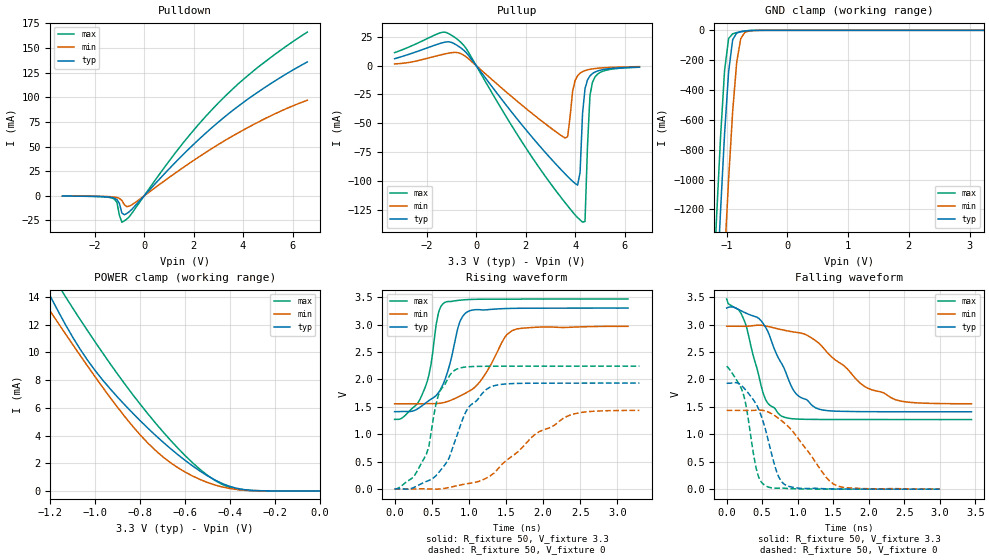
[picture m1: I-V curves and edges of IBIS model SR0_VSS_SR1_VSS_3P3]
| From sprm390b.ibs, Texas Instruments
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|   Model Cell SR0_VSS_SR1_VSS_3P3
|SR0_VSS_SR1_VSS_3P3
[Model]   SR0_VSS_SR1_VSS_3P3
Model_type   I/O
Polarity   Non-Inverting
Enable   Active-Low
Vinl =  0.8V
Vinh =  2V
Cref =  5.0000pF
Rref =  100.0000M
Vref =  0V
Vmeas =  1.65
C_comp   2.088321p   2.017362p   2.221145p
[Model Spec]
Vinl   0.8V   0.8V   0.8V
Vinh   2V   2V   2V
[Temperature Range]   25   125   -40
[Voltage Range]   3.3   2.97   3.465
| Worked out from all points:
|   slope of the pulldown table from 0 to 0.495 V, typ, clamps not added: 36.4 ohm
|   slope of the pullup table from 0 to 0.495 V, typ, clamps not added: 34.9 ohm
|   GND clamp passes 1 mA (typ) near -0.57 V on its own axis
|   POWER clamp passes 1 mA (typ) near -0.49 V on its own axis
|   rising waveform, R_fixture 50, V_fixture 3.3: 20-80 % time 244ps typ, 387ps min, 197ps max; typ from 1.41 V to 3.3 V
|   rising waveform, R_fixture 50, V_fixture 0: 20-80 % time 393ps typ, 793ps min, 263ps max; typ from 0 V to 1.93 V
|   falling waveform, R_fixture 50, V_fixture 3.3: 20-80 % time 387ps typ, 715ps min, 264ps max; typ from 3.3 V to 1.41 V
|   falling waveform, R_fixture 50, V_fixture 0: 20-80 % time 270ps typ, 497ps min, 185ps max; typ from 1.93 V to 0 V
[POWER_clamp]
|   voltage   I(typ)   I(min)   I(max)
-3.3V     86.08mA    64.51mA    104.3mA
-1.267V   16.23mA    14.61mA    17.94mA
-1.233V   15.14mA    13.79mA    16.86mA
-1.2V     14.07mA    12.98mA    15.86mA
-1.133V   12.04mA    11.37mA    14.06mA
-1V       8.693mA    8.239mA    10.76mA
-866.7mV  6.192mA    5.342mA    7.695mA
-766.7mV  4.556mA    3.483mA    5.603mA
-633.3mV  2.644mA    1.698mA    3.12mA
-500mV    1.095mA    613.6uA    1.135mA
-366.7mV  181.9uA    101.9uA    111.5uA
-11.55fV  484.7nA    452.9nA    508.6nA
[Pulldown]
|   voltage   I(typ)   I(min)   I(max)
-3.3V     -240.7uA   -171.6uA   -267.5uA
-1.3V     -1.697mA   -968uA     -2.239mA
-1.1V     -3.762mA   -1.687mA   -6.636mA
-1V       -7.727mA   -2.567mA   -19.64mA
-900mV    -17.44mA   -4.637mA   -26.73mA
-800mV    -19.19mA   -8.992mA   -25.39mA
-700mV    -17.88mA   -11mA      -23.57mA
-500mV    -13.74mA   -9.146mA   -17.83mA
1.4V      37.42mA    25.57mA    48.03mA
2.9V      72.6mA     50.52mA    91.53mA
4.6V      105.1mA    74.64mA    130.4mA
6.6V      135.8mA    96.92mA    166.1mA
[Pullup]
|   voltage   I(typ)   I(min)   I(max)
-3.3V     6.015mA    1.488mA    11.26mA
-1.4V     19.63mA    9.503mA    28.79mA
-700mV    16.55mA    11.01mA    21.71mA
3.6V      -93.97mA   -62.77mA   -119mA
4.1V      -103.6mA   -8.736mA   -131.8mA
4.2V      -92.66mA   -6.55mA    -133.7mA
4.3V      -41.55mA   -5.211mA   -135.8mA
4.4V      -19.91mA   -4.314mA   -135.1mA
4.5V      -12.4mA    -3.675mA   -69.72mA
4.6V      -8.868mA   -3.197mA   -25.86mA
4.7V      -6.864mA   -2.828mA   -14.55mA
6.6V      -1.25mA    -873.6uA   -1.41mA
[GND_clamp]
|   voltage   I(typ)   I(min)   I(max)
-3.3V     -22.46A    -23.25A    -22.02A
-1.233V   -2.372A    -3.255A    -1.856A
-1.167V   -1.78A     -2.658A    -1.268A
-1.1V     -1.214A    -2.077A    -719.3mA
-1.033V   -694.8mA   -1.519A    -269mA
-966.7mV  -277.7mA   -998.2mA   -54.71mA
-900mV    -62.85mA   -543.8mA   -23.11mA
-833.3mV  -17.76mA   -212.7mA   -15.05mA
-766.7mV  -9.254mA   -55.4mA    -9.029mA
-700mV    -5.096mA   -13.88mA   -4.435mA
-633.3mV  -2.353mA   -4.844mA   -1.587mA
3.233V    464.9nA    13.45uA    453.9nA
[Ramp]
| variable   typ   min   max
dV/dt_f   1.530224/0.7195842n   1.148064/1.235031n   1.776345/0.4937041n
dV/dt_r   1.548496/0.664374n   1.151877/1.13807n   1.796222/0.4649104n
R_load = 50
[Rising Waveform]
R_fixture = 50
V_fixture = 3.3
V_fixture_min = 2.97
V_fixture_max = 3.465
|   time   V(typ)   V(min)   V(max)
0s        1.411V     1.554V     1.269V
364ps     1.513V     1.555V     1.7V
462ps     1.612V     1.557V     2.077V
588ps     1.75V      1.56V      3.199V
679ps     1.998V     1.582V     3.405V
875ps     3.036V     1.691V     3.444V
1.015ns   3.253V     1.793V     3.457V
1.197ns   3.266V     2.047V     3.462V
1.582ns   3.295V     2.889V     3.464V
3.143ns   3.3V       2.967V     3.465V
[Rising Waveform]
R_fixture = 50
V_fixture = 0
V_fixture_min = 0
V_fixture_max = 0
|   time   V(typ)   V(min)   V(max)
0s        5.618uV    6.879uV    4.844uV
238ps     14.62mV    -57.69uV   199mV
427ps     136.4mV    1.76mV     629.7mV
588ps     289.8mV    -3.133mV   1.703V
826ps     922.2mV    53.85mV    2.179V
987ps     1.469V     98.26mV    2.229V
1.337ns   1.882V     286.6mV    2.239V
1.883ns   1.929V     986.8mV    2.241V
2.31ns    1.931V     1.317V     2.241V
3.297ns   1.931V     1.433V     2.241V
[Falling Waveform]
R_fixture = 50
V_fixture = 3.3
V_fixture_min = 2.97
V_fixture_max = 3.465
|   time   V(typ)   V(min)   V(max)
0s        3.3V       2.97V      3.465V
252ps     3.22V      2.969V     3.059V
455ps     3.11V      2.989V     2.052V
546ps     2.954V     2.975V     1.636V
777ps     2.281V     2.906V     1.329V
973ps     1.744V     2.859V     1.279V
1.309ns   1.454V     2.646V     1.271V
1.932ns   1.413V     1.878V     1.269V
2.366ns   1.411V     1.635V     1.269V
3.444ns   1.411V     1.557V     1.269V
[Falling Waveform]
R_fixture = 50
V_fixture = 0
V_fixture_min = 0
V_fixture_max = 0
|   time   V(typ)   V(min)   V(max)
0s        1.931V     1.436V     2.241V
224ps     1.869V     1.436V     1.776V
280ps     1.788V     1.435V     1.468V
420ps     1.538V     1.44V      353.3mV
546ps     1.086V     1.425V     63.16mV
721ps     258.1mV    1.299V     17.03mV
875ps     50.25mV    1.131V     10.76mV
1.407ns   7.252mV    206.3mV    1.482mV
1.575ns   3.763mV    51.31mV    1.042mV
2.996ns   371uV      3.039mV    124.8uV
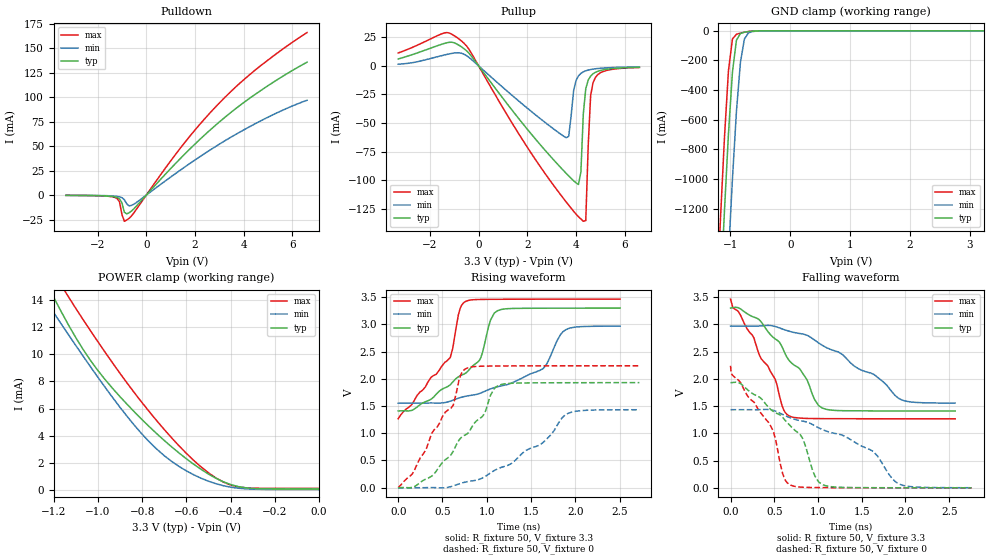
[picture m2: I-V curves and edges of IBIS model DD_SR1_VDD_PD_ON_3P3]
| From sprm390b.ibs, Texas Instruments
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|   Model Cell DD_SR1_VDD_PD_ON_3P3
|SR0_VDD_SR1_VDD_PD_ON_3P3
[Model]   DD_SR1_VDD_PD_ON_3P3
Model_type   I/O
Polarity   Non-Inverting
Enable   Active-Low
Vinl =  0.8V
Vinh =  2V
Cref =  5.0000pF
Rref =  100.0000M
Vref =  0V
Vmeas =  1.65
C_comp   2.113745p   2.040636p   2.247812p
[Model Spec]
Vinl   0.8V   0.8V   0.8V
Vinh   2V   2V   2V
[Temperature Range]   25   125   -40
[Voltage Range]   3.3   2.97   3.465
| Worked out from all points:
|   slope of the pulldown table from 0 to 0.495 V, typ, clamps not added: 36.4 ohm
|   slope of the pullup table from 0 to 0.495 V, typ, clamps not added: 34.9 ohm
|   GND clamp passes 1 mA (typ) near -0.57 V on its own axis
|   POWER clamp passes 1 mA (typ) near -0.48 V on its own axis
|   rising waveform, R_fixture 50, V_fixture 3.3: 20-80 % time 539ps typ, 708ps min, 443ps max; typ from 1.41 V to 3.3 V
|   rising waveform, R_fixture 50, V_fixture 0: 20-80 % time 549ps typ, 739ps min, 445ps max; typ from 0 V to 1.93 V
|   falling waveform, R_fixture 50, V_fixture 3.3: 20-80 % time 516ps typ, 825ps min, 402ps max; typ from 3.3 V to 1.41 V
|   falling waveform, R_fixture 50, V_fixture 0: 20-80 % time 526ps typ, 842ps min, 410ps max; typ from 1.93 V to 0.001 V
[POWER_clamp]
|   voltage   I(typ)   I(min)   I(max)
-3.3V     86.18mA    64.56mA    104.4mA
-1.267V   16.33mA    14.66mA    18.08mA
-1.233V   15.23mA    13.85mA    17mA
-1.2V     14.16mA    13.03mA    16mA
-1.133V   12.14mA    11.42mA    14.2mA
-1V       8.786mA    8.291mA    10.9mA
-866.7mV  6.286mA    5.394mA    7.837mA
-766.7mV  4.65mA     3.535mA    5.745mA
-633.3mV  2.737mA    1.75mA     3.262mA
-500mV    1.189mA    665.2uA    1.278mA
-366.7mV  275.7uA    153.6uA    253.8uA
-11.55fV  94.2uA     52.09uA    142.8uA
[Pulldown]
|   voltage   I(typ)   I(min)   I(max)
-3.3V     -240.7uA   -171.6uA   -267.5uA
-1.3V     -1.697mA   -968uA     -2.239mA
-1.1V     -3.762mA   -1.687mA   -6.637mA
-1V       -7.728mA   -2.567mA   -19.64mA
-900mV    -17.44mA   -4.637mA   -26.73mA
-800mV    -19.19mA   -8.992mA   -25.39mA
-700mV    -17.88mA   -11mA      -23.57mA
-500mV    -13.74mA   -9.146mA   -17.83mA
1.4V      37.42mA    25.57mA    48.03mA
2.9V      72.6mA     50.52mA    91.53mA
4.6V      105.1mA    74.64mA    130.4mA
6.6V      135.8mA    96.92mA    166.1mA
[Pullup]
|   voltage   I(typ)   I(min)   I(max)
-3.3V     6.015mA    1.488mA    11.26mA
-1.4V     19.63mA    9.503mA    28.79mA
-700mV    16.55mA    11.01mA    21.71mA
3.6V      -93.97mA   -62.77mA   -119mA
4.1V      -103.6mA   -8.736mA   -131.8mA
4.2V      -92.66mA   -6.551mA   -133.7mA
4.3V      -41.56mA   -5.211mA   -135.8mA
4.4V      -19.91mA   -4.314mA   -135.1mA
4.5V      -12.4mA    -3.675mA   -69.73mA
4.6V      -8.869mA   -3.197mA   -25.87mA
4.7V      -6.864mA   -2.828mA   -14.55mA
6.6V      -1.25mA    -873.6uA   -1.41mA
[GND_clamp]
|   voltage   I(typ)   I(min)   I(max)
-3.3V     -22.46A    -23.25A    -22.02A
-1.233V   -2.372A    -3.255A    -1.856A
-1.167V   -1.78A     -2.658A    -1.268A
-1.1V     -1.214A    -2.077A    -719.3mA
-1.033V   -694.9mA   -1.519A    -269mA
-966.7mV  -277.7mA   -998.2mA   -54.82mA
-900mV    -62.93mA   -543.8mA   -23.21mA
-833.3mV  -17.83mA   -212.7mA   -15.14mA
-766.7mV  -9.317mA   -55.45mA   -9.115mA
-700mV    -5.152mA   -13.93mA   -4.514mA
-633.3mV  -2.404mA   -4.879mA   -1.658mA
3.233V    94.16uA    65.13uA    142.7uA
[Ramp]
| variable   typ   min   max
dV/dt_f   1.523355/0.6834145n   1.142835/1.117289n   1.768965/0.5169915n
dV/dt_r   1.545562/0.6945306n   1.149676/0.9660131n   1.792774/0.5502105n
R_load = 50
[Rising Waveform]
R_fixture = 50
V_fixture = 3.3
V_fixture_min = 2.97
V_fixture_max = 3.465
|   time   V(typ)   V(min)   V(max)
0s        1.409V     1.553V     1.267V
588ps     1.89V      1.589V     2.391V
679ps     2.036V     1.643V     3.171V
749ps     2.091V     1.675V     3.408V
931ps     2.381V     1.738V     3.456V
1.043ns   3.081V     1.814V     3.458V
1.12ns    3.248V     1.853V     3.459V
1.638ns   3.295V     2.189V     3.462V
1.89ns    3.296V     2.899V     3.462V
2.506ns   3.297V     2.966V     3.462V
[Rising Waveform]
R_fixture = 50
V_fixture = 0
V_fixture_min = 0
V_fixture_max = 0
|   time   V(typ)   V(min)   V(max)
0s        5.609uV    6.87uV     4.835uV
161ps     4.625mV    -39.19uV   257.1mV
378ps     211.5mV    2.892mV    996.8mV
623ps     674.4mV    34.16mV    1.519V
707ps     914.4mV    80.58mV    2.077V
777ps     988.2mV    109.6mV    2.195V
1.162ns   1.894V     372.6mV    2.235V
1.645ns   1.926V     843.9mV    2.238V
1.918ns   1.928V     1.365V     2.238V
2.723ns   1.929V     1.431V     2.239V
[Falling Waveform]
R_fixture = 50
V_fixture = 3.3
V_fixture_min = 2.97
V_fixture_max = 3.465
|   time   V(typ)   V(min)   V(max)
0s        3.298V     2.969V     3.463V
322ps     3.094V     2.969V     2.465V
511ps     2.732V     2.96V      1.992V
588ps     2.592V     2.917V     1.513V
665ps     2.348V     2.876V     1.325V
868ps     1.999V     2.804V     1.274V
1.008ns   1.508V     2.658V     1.271V
1.099ns   1.439V     2.571V     1.27V
1.96ns    1.41V      1.612V     1.267V
2.569ns   1.41V      1.556V     1.267V
[Falling Waveform]
R_fixture = 50
V_fixture = 0
V_fixture_min = 0
V_fixture_max = 0
|   time   V(typ)   V(min)   V(max)
0s        1.93V      1.434V     2.239V
462ps     1.435V     1.433V     1.127V
595ps     1.295V     1.347V     267.1mV
686ps     1.135V     1.283V     51.41mV
819ps     922.9mV    1.226V     12.55mV
966ps     212.7mV    1.137V     6.108mV
1.057ns   55.56mV    1.066V     4.704mV
1.631ns   3.37mV     669.1mV    1.466mV
1.932ns   2.062mV    67.18mV    841.4uV
2.758ns   753.9uV    2.997mV    245.1uV
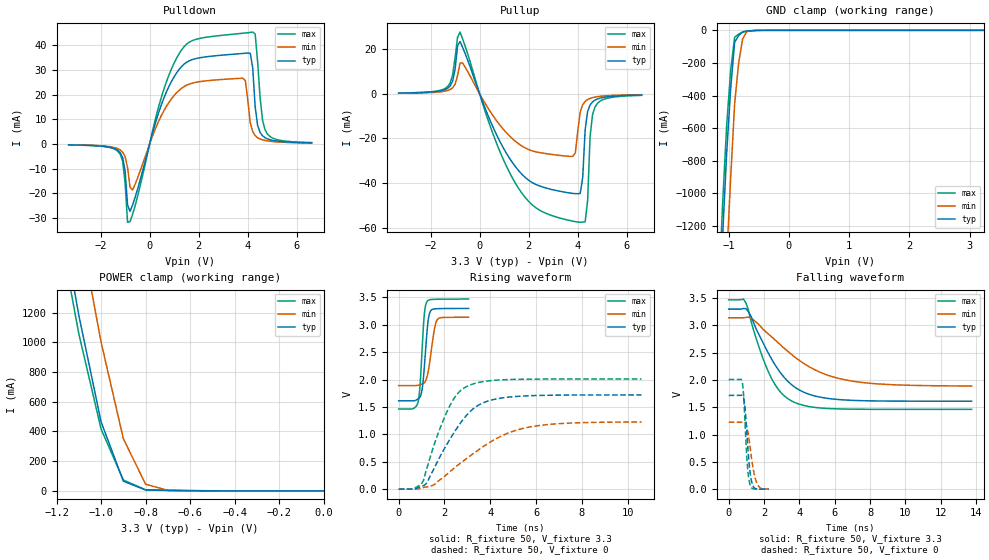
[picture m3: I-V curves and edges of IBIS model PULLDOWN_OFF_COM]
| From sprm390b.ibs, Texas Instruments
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|   Model Cell PULLDOWN_OFF_COM
[Model]   PULLDOWN_OFF_COM
Model_type   I/O
Polarity   Non-Inverting
Enable   Active-Low
Vinl =  0.8
Vinh =  2
Cref =  15.0000pF
Rref =  100.0000M
Vref =  0V
Vmeas =  1.65
C_comp   0.8695239p   0.8563616p   0.8781626p
[Model Spec]
Vinl   0.8   0.8   0.8
Vinh   2   2   2
[Temperature Range]   25   105   0
[Voltage Range]   3.3   3.14   3.47
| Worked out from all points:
|   slope of the pulldown table from 0 to 0.495 V, typ, clamps not added: 30.2 ohm
|   slope of the pullup table from 0 to 0.495 V, typ, clamps not added: 36.2 ohm
|   GND clamp passes 1 mA (typ) near -0.57 V on its own axis
|   POWER clamp passes 1 mA (typ) near -0.52 V on its own axis
|   rising waveform, R_fixture 50, V_fixture 3.3: 20-80 % time 195ps typ, 262ps min, 169ps max; typ from 1.61 V to 3.3 V
|   rising waveform, R_fixture 50, V_fixture 0: 20-80 % time 1.52ns typ, 2.51ns min, 1.1ns max; typ from 0 V to 1.72 V
|   falling waveform, R_fixture 50, V_fixture 3.3: 20-80 % time 1.92ns typ, 3.11ns min, 1.46ns max; typ from 3.3 V to 1.61 V
|   falling waveform, R_fixture 50, V_fixture 0: 20-80 % time 242ps typ, 346ps min, 204ps max; typ from 1.72 V to 0.002 V
[POWER_clamp]
|   voltage   I(typ)   I(min)   I(max)
-3.3V     22.37A     22.96A     22.21A
-1.133V   1.464A     2.096A     1.329A
-1.1V     1.183A     1.806A     1.058A
-1.067V   943.8mA    1.538A     844.6mA
-1.033V   704.5mA    1.27A      630.9mA
-1V       465.3mA    1.002A     417.3mA
-900mV    65.74mA    351.8mA    73.25mA
-800mV    6.466mA    45.05mA    7.737mA
-700mV    3.149mA    4.035mA    4.004mA
-11.55fV  473.5pA    5.468nA    843.1pA
[Pulldown]
|   voltage   I(typ)   I(min)   I(max)
-3.3V     -379.4uA   -345.5uA   -405uA
-1.3V     -2.568mA   -1.909mA   -2.955mA
-1.1V     -5.533mA   -3.354mA   -7.005mA
-900mV    -24.8mA    -9.58mA    -31.78mA
-800mV    -27.41mA   -17.54mA   -31.56mA
400mV     13.7mA     9.942mA    16.3mA
1.2V      30.22mA    21.74mA    36.6mA
3.8V      36.73mA    26.64mA    44.94mA
4.2V      30.93mA    4.999mA    45.4mA
4.4V      7.557mA    2.538mA    33.36mA
4.7V      2.533mA    1.415mA    5.821mA
6.6V      436uA      357.4uA    548uA
[Pullup]
|   voltage   I(typ)   I(min)   I(max)
-3.3V     352.6uA    268.9uA    395.9uA
-1.3V     2.559mA    1.54mA     3.337mA
-800mV    23.47mA    13.87mA    27.72mA
1.5V      -33.25mA   -21.66mA   -40.85mA
3.8V      -44.66mA   -28.01mA   -57.09mA
4.1V      -44.61mA   -8.068mA   -57.55mA
4.2V      -37.49mA   -4.806mA   -57.56mA
4.3V      -15.99mA   -3.326mA   -57.36mA
4.4V      -7.897mA   -2.517mA   -47.82mA
4.5V      -4.997mA   -2.014mA   -19.22mA
4.7V      -2.803mA   -1.431mA   -5.878mA
6.6V      -515.4uA   -371.2uA   -665.4uA
[GND_clamp]
|   voltage   I(typ)   I(min)   I(max)
-3.3V     -22.52A    -23.16A    -22.34A
-1.167V   -1.845A    -2.552A    -1.643A
-1.1V     -1.269A    -1.966A    -1.072A
-1.033V   -763.9mA   -1.418A    -593.7mA
-966.7mV  -365.3mA   -913.8mA   -250.4mA
-900mV    -73.57mA   -452.5mA   -42.45mA
-833.3mV  -32.62mA   -200.8mA   -23.3mA
-766.7mV  -9.66mA    -52.9mA    -11.11mA
-700mV    -4.683mA   -8.87mA    -5.886mA
-500mV    -175.5uA   -431.3uA   -205.5uA
3.233V    -419pA     127.5nA    -192.1pA
[Ramp]
| variable   typ   min   max
dV/dt_f   1.022939/1.92642n   0.7589381/3.145801n   1.215389/1.460336n
dV/dt_r   1.031672/1.51958n   0.737178/2.519213n   1.206129/1.098784n
R_load = 50
[Rising Waveform]
R_fixture = 50
V_fixture = 3.3
V_fixture_min = 3.14
V_fixture_max = 3.47
|   time   V(typ)   V(min)   V(max)
0s        1.612V     1.889V     1.463V
836ps     1.644V     1.894V     1.57V
932ps     1.681V     1.906V     1.883V
1.024ns   1.819V     1.918V     2.547V
1.12ns    2.221V     1.939V     3.194V
1.244ns   2.902V     2.059V     3.428V
1.368ns   3.23V      2.354V     3.457V
1.556ns   3.289V     2.907V     3.463V
1.68ns    3.292V     3.088V     3.465V
3.056ns   3.298V     3.137V     3.468V
[Rising Waveform]
R_fixture = 50
V_fixture = 0
V_fixture_min = 0
V_fixture_max = 0
|   time   V(typ)   V(min)   V(max)
0s        97.46nV    174.5nV    117.1nV
972ps     47.87mV    17.9mV     81.81mV
1.188ns   91.08mV    38.46mV    320.6mV
1.62ns    440.4mV    104mV      897.3mV
2.164ns   859.2mV    291.6mV    1.462V
2.596ns   1.145V     441.3mV    1.755V
3.028ns   1.377V     577.3mV    1.884V
3.896ns   1.608V     832.1mV    1.974V
5.628ns   1.703V     1.126V     2.006V
10.61ns   1.719V     1.225V     2.01V
[Falling Waveform]
R_fixture = 50
V_fixture = 3.3
V_fixture_min = 3.14
V_fixture_max = 3.47
|   time   V(typ)   V(min)   V(max)
0s        3.3V       3.14V      3.47V
840ps     3.311V     3.14V      3.484V
1.26ns    3.171V     3.138V     3.086V
1.82ns    2.764V     2.977V     2.506V
2.38ns    2.413V     2.805V     2.059V
2.944ns   2.128V     2.641V     1.776V
3.784ns   1.861V     2.411V     1.583V
5.328ns   1.678V     2.123V     1.485V
7.012ns   1.628V     1.98V      1.467V
13.75ns   1.612V     1.892V     1.463V
[Falling Waveform]
R_fixture = 50
V_fixture = 0
V_fixture_min = 0
V_fixture_max = 0
|   time   V(typ)   V(min)   V(max)
0s        1.719V     1.228V     2.01V
760ps     1.723V     1.229V     1.969V
832ps     1.685V     1.235V     1.782V
900ps     1.57V      1.231V     1.393V
992ps     1.216V     1.183V     782.2mV
1.064ns   862.4mV    1.091V     426.4mV
1.224ns   280.4mV    738mV      67.35mV
1.388ns   53.46mV    373mV      8.465mV
1.62ns    5.629mV    95.2mV     2.683mV
2.272ns   1.702mV    3.189mV    1.369mV
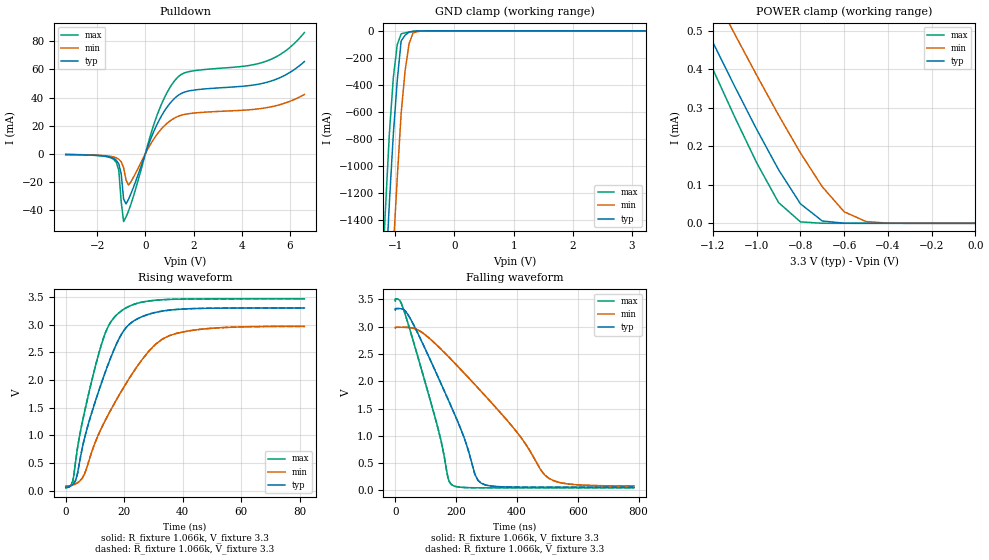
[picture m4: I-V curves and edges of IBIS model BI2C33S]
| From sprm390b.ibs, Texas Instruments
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|   Model Cell BI2C33S
|BI2C33S
[Model]   BI2C33S
Model_type   I/O_open_drain
Polarity   Non-Inverting
Enable   Active-Low
Vinl =  0.99
Vinh =  2.31
Cref =  400pF
Rref =  528
Vref =  1.8V
Vmeas =  1.65
C_comp   5.420733p   4.31035p   6.36532p
[Model Spec]
Vinl   0.99   0.891   1.0395
Vinh   2.31   2.079   2.4255
[Temperature Range]   25   125   -40
[Voltage Range]   3.3   2.97   3.465
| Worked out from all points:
|   slope of the pulldown table from 0 to 0.495 V, typ, clamps not added: 23.3 ohm
|   GND clamp passes 1 mA (typ) near -0.57 V on its own axis
|   POWER clamp passes 1 mA (typ) near -1.65 V on its own axis
|   rising waveform, R_fixture 1.066k, V_fixture 3.3: 20-80 % time 12ns typ, 17.8ns min, 9.17ns max; typ from 0.06 V to 3.3 V
|   rising waveform, R_fixture 1.066k, V_fixture 3.3: 20-80 % time 12ns typ, 17.8ns min, 9.17ns max; typ from 0.06 V to 3.3 V
|   falling waveform, R_fixture 1.066k, V_fixture 3.3: 20-80 % time 148ns typ, 265ns min, 101ns max; typ from 3.3 V to 0.06 V
|   falling waveform, R_fixture 1.066k, V_fixture 3.3: 20-80 % time 148ns typ, 265ns min, 101ns max; typ from 3.3 V to 0.06 V
[POWER_clamp]
|   voltage   I(typ)   I(min)   I(max)
-3.3V     3.01mA     2.987mA    3.173mA
-1.3V     585.8uA    709uA      526.5uA
-1.267V   546.9uA    672.4uA    484.2uA
-1.233V   508.1uA    635.8uA    441.9uA
-1.133V   393uA      527uA      316.8uA
-1.1V     354.9uA    490.9uA    275.5uA
-900mV    139.2uA    281.1uA    53.85uA
-800mV    50.63uA    182.8uA    3.742uA
-700mV    6.043uA    94.72uA    48.27nA
-600mV    243.3nA    29.91uA    437.4pA
-500mV    6.252nA    4.517uA    33.22pA
-11.55fV  261.1pA    12.69nA    13.85pA
[Pulldown]
|   voltage   I(typ)   I(min)   I(max)
-3.3V     -492uA     -429.3uA   -500uA
-1.3V     -3.315mA   -2.261mA   -4.076mA
-1.1V     -7.123mA   -3.82mA    -11.69mA
-1V       -14.13mA   -5.651mA   -34.01mA
-900mV    -32.12mA   -9.78mA    -48.13mA
-800mV    -35.62mA   -18.45mA   -44.86mA
-700mV    -32.38mA   -22.18mA   -40.77mA
500mV     21.44mA    14.19mA    28mA
1.3V      40.76mA    26.23mA    53.69mA
1.9V      45.03mA    28.79mA    58.77mA
5V        50.69mA    32.76mA    65.78mA
6.6V      65.61mA    42.22mA    86.24mA
[GND_clamp]
|   voltage   I(typ)   I(min)   I(max)
-3.3V     -22.54A    -23.35A    -22.08A
-1.233V   -2.448A    -3.354A    -1.916A
-1.167V   -1.857A    -2.757A    -1.332A
-1.1V     -1.28A     -2.169A    -767.6mA
-1.033V   -772.1mA   -1.614A    -351.6mA
-966.7mV  -370.4mA   -1.094A    -103.1mA
-900mV    -74.5mA    -609.3mA   -21.97mA
-833.3mV  -32.63mA   -294.9mA   -14.51mA
-766.7mV  -9.28mA    -96.93mA   -8.456mA
-700mV    -4.457mA   -15.42mA   -3.821mA
-433.3mV  -64.85uA   -255.7uA   -19.87uA
3.233V    245.2pA    35.59nA    9.697pA
[Ramp]
| variable   typ   min   max
dV/dt_f   1.961065/0.1498822u   1.742881/0.2670712u   2.074498/0.1020424u
dV/dt_r  81.34522m/1.778974n   56.69538m/4.113156n   97.10233m/1.048033n
R_load = 1.066k
[Rising Waveform]
R_fixture = 1.066k
V_fixture = 3.3
V_fixture_min = 2.97
V_fixture_max = 3.465
|   time   V(typ)   V(min)   V(max)
0s        60.23mV    81mV       48.5mV
2.4ns     107.6mV    101mV      170.4mV
3.3ns     176.7mV    119.3mV    497.3mV
6.3ns     921.4mV    286.3mV    1.393V
12ns      1.91V      1.106V     2.605V
14.7ns    2.31V      1.388V     2.985V
18.3ns    2.753V     1.729V     3.218V
24.3ns    3.099V     2.235V     3.383V
35.4ns    3.261V     2.799V     3.455V
81.6ns    3.3V       2.967V     3.465V
[Rising Waveform]
R_fixture = 1.066k
V_fixture = 3.3
V_fixture_min = 2.97
V_fixture_max = 3.465
|   time   V(typ)   V(min)   V(max)
0s        60.23mV    81mV       48.5mV
2.4ns     107.6mV    101mV      170.4mV
3.3ns     176.7mV    119.3mV    497.3mV
6.3ns     921.4mV    286.3mV    1.393V
12ns      1.91V      1.106V     2.605V
14.7ns    2.31V      1.388V     2.985V
18.3ns    2.753V     1.729V     3.218V
24.3ns    3.099V     2.235V     3.383V
35.4ns    3.261V     2.799V     3.455V
81.6ns    3.3V       2.967V     3.465V
[Falling Waveform]
R_fixture = 1.066k
V_fixture = 3.3
V_fixture_min = 2.97
V_fixture_max = 3.465
|   time   V(typ)   V(min)   V(max)
0s        3.3V       2.97V      3.465V
14.1ns    3.328V     2.986V     3.483V
41.1ns    3.222V     2.983V     3.069V
143.1ns   2.044V     2.624V     1.076V
173.4ns   1.668V     2.456V     226.9mV
186ns     1.509V     2.384V     104.5mV
261.6ns   297.6mV    1.938V     49.89mV
293.1ns   107.6mV    1.747V     48.87mV
505.2ns   60.33mV    222.9mV    48.5mV
784.8ns   60.23mV    83.98mV    48.5mV
[Falling Waveform]
R_fixture = 1.066k
V_fixture = 3.3
V_fixture_min = 2.97
V_fixture_max = 3.465
|   time   V(typ)   V(min)   V(max)
0s        3.3V       2.97V      3.465V
14.1ns    3.328V     2.986V     3.483V
41.1ns    3.222V     2.983V     3.069V
143.1ns   2.044V     2.624V     1.076V
173.4ns   1.668V     2.456V     226.9mV
186ns     1.509V     2.384V     104.5mV
261.6ns   297.6mV    1.938V     49.89mV
293.1ns   107.6mV    1.747V     48.87mV
505.2ns   60.33mV    222.9mV    48.5mV
784.8ns   60.23mV    83.98mV    48.5mV
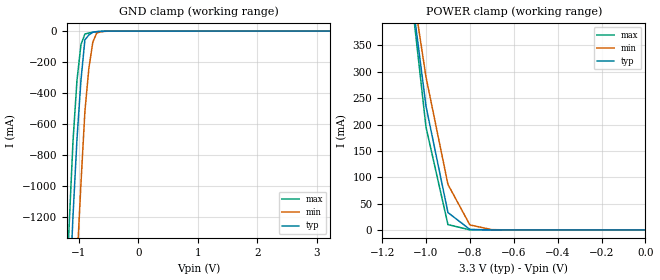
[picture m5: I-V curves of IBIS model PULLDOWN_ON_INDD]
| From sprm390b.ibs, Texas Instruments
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|   Model Cell PULLDOWN_ON_INDD
[Model]   PULLDOWN_ON_INDD
Model_type   Input
Polarity   Non-Inverting
Vinl =  0.8
Vinh =  2
C_comp   0.8695239p   0.8584917p   0.8767336p
[Model Spec]
Vinl   0.8   0.8   0.8
Vinh   2   2   2
[Temperature Range]   25   125   -40
[Voltage Range]   3.3   3.14   3.47
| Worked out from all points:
|   GND clamp passes 1 mA (typ) near -0.58 V on its own axis
|   POWER clamp passes 1 mA (typ) near -0.79 V on its own axis
[POWER_clamp]
|   voltage   I(typ)   I(min)   I(max)
-3.3V     9.572A     8.115A     10.87A
-1.067V   452.2mA    472.9mA    444.7mA
-1.033V   343.5mA    381.5mA    319.9mA
-1V       234.9mA    290.2mA    195.1mA
-900mV    33.1mA     86.51mA    10.28mA
-800mV    1.106mA    9.6mA      232.3uA
-700mV    117.1uA    663.9uA    143.6uA
-11.55fV  93.69uA    58.38uA    142.7uA
[GND_clamp]
|   voltage   I(typ)   I(min)   I(max)
-3.3V     -22.43A    -23.21A    -22A
-1.233V   -2.35A     -3.221A    -1.845A
-1.167V   -1.763A    -2.627A    -1.266A
-1.1V     -1.191A    -2.042A    -709.3mA
-1.033V   -696.7mA   -1.495A    -318mA
-966.7mV  -318.5mA   -986.5mA   -87.86mA
-900mV    -56.2mA    -518.4mA   -18.79mA
-833.3mV  -25.19mA   -240.3mA   -12.38mA
-766.7mV  -7.722mA   -71.26mA   -7.216mA
-700mV    -3.804mA   -11.24mA   -3.292mA
-433.3mV  -88.44uA   -235.1uA   -64.74uA
3.233V    93.67uA    58.39uA    142.6uA
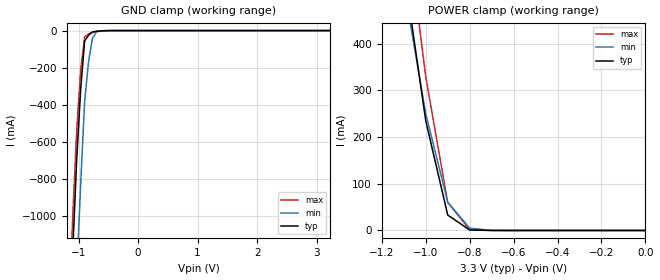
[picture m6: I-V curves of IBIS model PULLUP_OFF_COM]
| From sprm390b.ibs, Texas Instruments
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|   Model Cell PULLUP_OFF_COM
[Model]   PULLUP_OFF_COM
Model_type   Input
Polarity   Non-Inverting
Vinl =  0.8
Vinh =  2
C_comp   0.8695239p   0.8563616p   0.8781626p
[Model Spec]
Vinl   0.8   0.8   0.8
Vinh   2   2   2
[Temperature Range]   25   105   0
[Voltage Range]   3.3   3.14   3.47
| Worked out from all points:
|   GND clamp passes 1 mA (typ) near -0.58 V on its own axis
|   POWER clamp passes 1 mA (typ) near -0.80 V on its own axis
[POWER_clamp]
|   voltage   I(typ)   I(min)   I(max)
-3.3V     9.572A     8.243A     10.54A
-1.067V   452.2mA    433.3mA    579.4mA
-1.033V   343.6mA    341.7mA    454.3mA
-1V       234.9mA    250.2mA    329.2mA
-900mV    33.06mA    60.43mA    60.04mA
-800mV    1.024mA    4.944mA    1.663mA
-700mV    26.08uA    273.3uA    30.03uA
-11.55fV  365.2pA    4.314nA    655.6pA
[GND_clamp]
|   voltage   I(typ)   I(min)   I(max)
-3.3V     -22.43A    -23.04A    -22.26A
-1.167V   -1.763A    -2.446A    -1.569A
-1.1V     -1.191A    -1.863A    -1.003A
-1.033V   -696.7mA   -1.322A    -538mA
-966.7mV  -318.5mA   -829.3mA   -215mA
-900mV    -56.13mA   -384.9mA   -33.48mA
-833.3mV  -25.12mA   -165.5mA   -18.5mA
-766.7mV  -7.66mA    -39.4mA    -8.911mA
-700mV    -3.748mA   -6.724mA   -4.715mA
-633.3mV  -1.908mA   -3.327mA   -2.393mA
3.233V    344.9pA    4.626nA    502.8pA
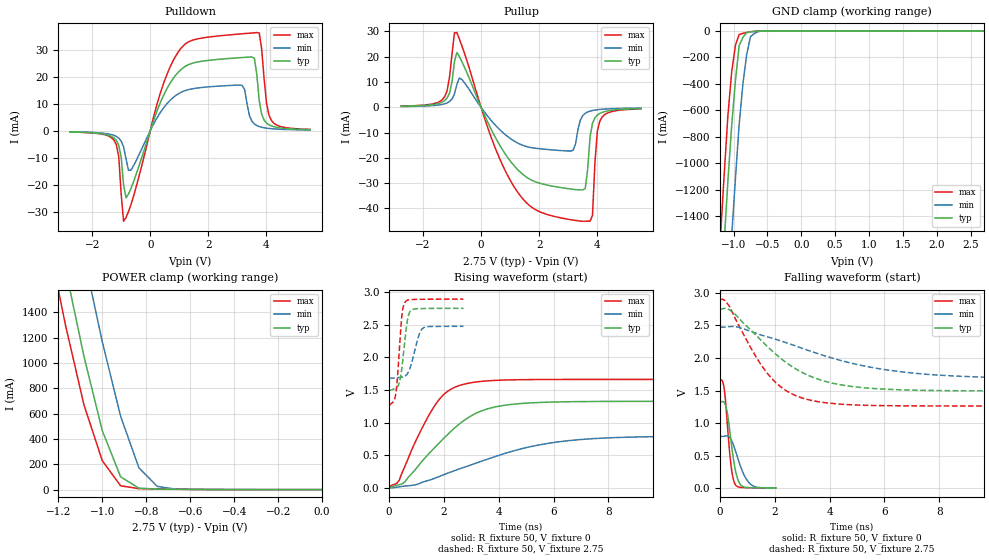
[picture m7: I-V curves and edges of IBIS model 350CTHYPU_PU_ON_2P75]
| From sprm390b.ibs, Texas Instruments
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|BC3350CTHYPU_PU_OFF_3P3; CELL IN NORMAL MODE WITH PULLUP DISABLED
|   Model Cell 350CTHYPU_PU_ON_2P75
|BC3350CTHYPU_PU_ON_2P75
[Model]   350CTHYPU_PU_ON_2P75
Model_type   I/O
Polarity   Non-Inverting
Enable   Active-Low
Vinl =  0.7V
Vinh =  1.7V
Cref =  15.0000pF
Rref =  100.0000M
Vref =  0V
Vmeas =  1.375
C_comp   0.8815254p   0.8700002p   0.8886429p
[Model Spec]
Vinl   0.7V   0.7V   0.7V
Vinh   1.7V   1.7V   1.7V
[Temperature Range]   25   125   -40
[Voltage Range]   2.75   2.475   2.89
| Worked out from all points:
|   slope of the pulldown table from 0 to 0.412 V, typ, clamps not added: 34.2 ohm
|   slope of the pullup table from 0 to 0.412 V, typ, clamps not added: 40.5 ohm
|   GND clamp passes 1 mA (typ) near -0.58 V on its own axis
|   POWER clamp passes 1 mA (typ) near -0.52 V on its own axis
|   rising waveform, R_fixture 50, V_fixture 0: 20-80 % time 1.9ns typ, 3.45ns min, 1.2ns max; typ from 0.003 V to 1.32 V
|   rising waveform, R_fixture 50, V_fixture 2.75: 20-80 % time 208ps typ, 303ps min, 165ps max; typ from 1.49 V to 2.75 V
|   falling waveform, R_fixture 50, V_fixture 0: 20-80 % time 263ps typ, 415ps min, 202ps max; typ from 1.32 V to 0.003 V
|   falling waveform, R_fixture 50, V_fixture 2.75: 20-80 % time 2.21ns typ, 3.92ns min, 1.52ns max; typ from 2.75 V to 1.49 V
[POWER_clamp]
|   voltage   I(typ)   I(min)   I(max)
-2.75V    16.94A     17.72A     16.52A
-1.194V   1.981A     2.806A     1.529A
-1.139V   1.509A     2.319A     1.084A
-1.083V   1.051A     1.84A      668.4mA
-1.056V   856mA      1.616A     521.6mA
-1.028V   660.7mA    1.391A     374.8mA
-1V       465.3mA    1.167A     228mA
-916.7mV  101.1mA    578.9mA    30.16mA
-833.3mV  11.48mA    171.8mA    7.352mA
-750mV    4.196mA    25.44mA    4.953mA
-666.7mV  2.696mA    3.777mA    3.266mA
0V        162.7pA    10.29nA    5.769pA
[Pulldown]
|   voltage   I(typ)   I(min)   I(max)
-2.75V    -442uA     -372.3uA   -461.5uA
-1.25V    -2.654mA   -1.707mA   -3.464mA
-1.083V   -5.414mA   -2.743mA   -9.572mA
-916.7mV  -20.11mA   -6.002mA   -33.59mA
-666.7mV  -21.47mA   -14.63mA   -27.52mA
1V        22.12mA    13.91mA    29.78mA
3.167V    27.16mA    16.8mA     35.98mA
3.667V    20.9mA     1.926mA    36.42mA
3.833V    6.158mA    1.295mA    30.36mA
4V        2.871mA    968.4uA    10.34mA
4.167V    1.802mA    770.5uA    3.863mA
5.5V      426.6uA    287.2uA    512.6uA
[Pullup]
|   voltage   I(typ)   I(min)   I(max)
-2.75V    418.2uA    298uA      474.9uA
-1.25V    2.701mA    1.416mA    4.261mA
-833.3mV  21.66mA    8.993mA    29.57mA
416.7mV   -10.28mA   -6.093mA   -13.97mA
1.167V    -23.49mA   -13.53mA   -31.97mA
3.167V    -32.42mA   -16.99mA   -44.58mA
3.5V      -32.66mA   -3.265mA   -45.07mA
3.583V    -32.13mA   -2.367mA   -45.05mA
3.833V    -6.324mA   -1.256mA   -42.67mA
4V        -3.057mA   -947.9uA   -9.451mA
4.083V    -2.401mA   -843.3uA   -5.52mA
5.5V      -494.4uA   -288.5uA   -602.6uA
[GND_clamp]
|   voltage   I(typ)   I(min)   I(max)
-2.75V    -17.09A    -17.92A    -16.63A
-1.194V   -2.087A    -2.985A    -1.564A
-1.139V   -1.603A    -2.493A    -1.092A
-1.083V   -1.133A    -2.009A    -639.3mA
-1.028V   -718.3mA   -1.55A     -312.5mA
-972.2mV  -377.7mA   -1.115A    -108.5mA
-916.7mV  -110.7mA   -705.2mA   -27.4mA
-861.1mV  -49.17mA   -398.3mA   -18.88mA
-805.6mV  -14.81mA   -178.2mA   -12.19mA
-750mV    -7.662mA   -44.87mA   -7.322mA
-638.9mV  -2.522mA   -6.13mA    -1.894mA
2.694V    -3.567uA   13.28uA    -16.98uA
[Ramp]
| variable   typ   min   max
dV/dt_f  0.7623938/2.22133n   0.4835484/3.980867n   0.9863653/1.528682n
dV/dt_r   0.794457/1.903685n   0.4760948/3.468563n   0.9954418/1.202246n
R_load = 50
[Rising Waveform]
R_fixture = 50
V_fixture = 0
V_fixture_min = 0
V_fixture_max = 0
|   time   V(typ)   V(min)   V(max)
0s        3.082mV    495.6uV    16.8mV
369ps     48.69mV    16.25mV    118.1mV
993ps     300.6mV    51.25mV    738.2mV
1.698ns   632.5mV    152.9mV    1.281V
2.088ns   798.3mV    217.7mV    1.464V
2.61ns    994mV      297.1mV    1.573V
3.174ns   1.143V     379.4mV    1.621V
3.885ns   1.24V      482.1mV    1.645V
6.519ns   1.318V     721.7mV    1.66V
13.17ns   1.325V     791.4mV    1.66V
[Rising Waveform]
R_fixture = 50
V_fixture = 2.75
V_fixture_min = 2.475
V_fixture_max = 2.89
|   time   V(typ)   V(min)   V(max)
0s        1.493V     1.68V      1.267V
240ps     1.528V     1.683V     1.437V
297ps     1.545V     1.687V     1.657V
369ps     1.609V     1.691V     2.092V
462ps     1.829V     1.695V     2.626V
579ps     2.277V     1.709V     2.841V
660ps     2.551V     1.744V     2.871V
744ps     2.684V     1.813V     2.88V
1.203ns   2.745V     2.435V     2.887V
2.712ns   2.748V     2.473V     2.889V
[Falling Waveform]
R_fixture = 50
V_fixture = 0
V_fixture_min = 0
V_fixture_max = 0
|   time   V(typ)   V(min)   V(max)
0s        1.325V     794.1mV    1.662V
132ps     1.326V     794.5mV    1.58V
234ps     1.226V     802.3mV    1.177V
336ps     952mV      785.9mV    622.1mV
402ps     725.1mV    747.3mV    349mV
465ps     521.3mV    689.6mV    177.2mV
546ps     307.4mV    595mV      64.07mV
741ps     55.81mV    343.3mV    10.18mV
1.11ns    5.752mV    61.24mV    4.174mV
2.031ns   2.942mV    3.404mV    2.601mV
[Falling Waveform]
R_fixture = 50
V_fixture = 2.75
V_fixture_min = 2.475
V_fixture_max = 2.89
|   time   V(typ)   V(min)   V(max)
0s        2.749V     2.475V     2.897V
177ps     2.764V     2.475V     2.884V
354ps     2.739V     2.483V     2.787V
1.239ns   2.382V     2.393V     2.072V
1.857ns   2.127V     2.311V     1.701V
2.481ns   1.91V      2.226V     1.481V
3.276ns   1.723V     2.109V     1.353V
4.827ns   1.561V     1.917V     1.28V
7.494ns   1.502V     1.751V     1.263V
16.3ns    1.494V     1.682V     1.262V
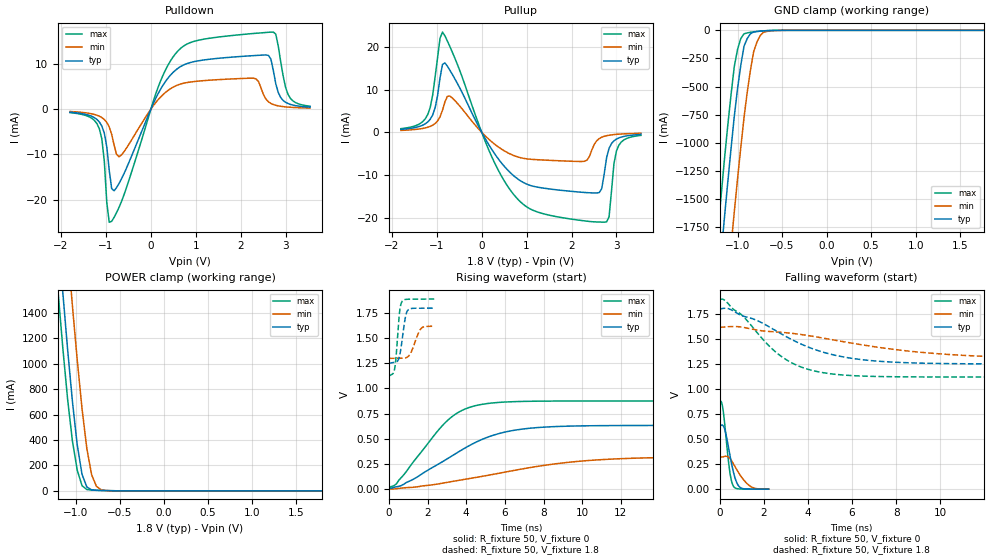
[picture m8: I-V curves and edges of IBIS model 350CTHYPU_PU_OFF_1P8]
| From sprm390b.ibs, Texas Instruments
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|   Model Cell 350CTHYPU_PU_OFF_1P8
|BC3350CTHYPU_PU_OFF_1P8
[Model]   350CTHYPU_PU_OFF_1P8
Model_type   I/O
Polarity   Non-Inverting
Enable   Active-Low
Vinl =  0.63
Vinh =  1.17
Cref =  15.0000pF
Rref =  100.0000M
Vref =  0V
Vmeas =  0.9
C_comp   1.505312p   1.488461p   1.520888p
[Model Spec]
Vinl   0.63   0.567   0.6615
Vinh   1.17   1.053   1.2285
[Temperature Range]   25   125   -40
[Voltage Range]   1.8   1.62   1.89
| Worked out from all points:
|   slope of the pulldown table from 0 to 0.27 V, typ, clamps not added: 51 ohm
|   slope of the pullup table from 0 to 0.27 V, typ, clamps not added: 57.1 ohm
|   GND clamp passes 1 mA (typ) near -0.58 V on its own axis
|   POWER clamp passes 1 mA (typ) near -0.52 V on its own axis
|   rising waveform, R_fixture 50, V_fixture 0: 20-80 % time 3.45ns typ, 5.9ns min, 2.21ns max; typ from 0.003 V to 0.633 V
|   rising waveform, R_fixture 50, V_fixture 1.8: 20-80 % time 247ps typ, 385ps min, 189ps max; typ from 1.25 V to 1.8 V
|   falling waveform, R_fixture 50, V_fixture 0: 20-80 % time 353ps typ, 588ps min, 255ps max; typ from 0.633 V to 0.001 V
|   falling waveform, R_fixture 50, V_fixture 1.8: 20-80 % time 3.19ns typ, 5.95ns min, 2.16ns max; typ from 1.8 V to 1.25 V
[POWER_clamp]
|   voltage   I(typ)   I(min)   I(max)
-1.8V     7.656A     8.472A     7.195A
-1.2V     2.026A     2.853A     1.569A
-1.145V   1.557A     2.372A     1.122A
-1.055V   838.8mA    1.603A     501mA
-1.036V   702.9mA    1.453A     391.9mA
-981.8mV  361.3mA    1.029A     163mA
-927.3mV  130mA      646.4mA    41.1mA
-872.7mV  30.97mA    333.2mA    10.82mA
-818.2mV  8.524mA    127mA      6.66mA
-763.6mV  4.546mA    35.75mA    5.186mA
-709.1mV  3.303mA    9.336mA    4.016mA
1.8V      62.93pA    6.445nA    994.8fA
[Pulldown]
|   voltage   I(typ)   I(min)   I(max)
-1.8V     -681.9uA   -516.6uA   -765.4uA
-1.145V   -2.846mA   -1.565mA   -4.381mA
-1.036V   -5.312mA   -2.288mA   -11.57mA
-927.3mV  -13.49mA   -3.93mA    -25mA
-872.7mV  -17.58mA   -5.576mA   -24.82mA
-709.1mV  -16.44mA   -10.53mA   -21.73mA
218.2mV   4.45mA     2.706mA    6.292mA
763.6mV   9.932mA    5.814mA    14.18mA
2.291V    11.85mA    6.843mA    16.75mA
2.727V    8.542mA    1.025mA    17.05mA
3.055V    1.241mA    457.6uA    3.265mA
3.545V    447.3uA    243.5uA    654.8uA
[Pullup]
|   voltage   I(typ)   I(min)   I(max)
-1.8V     683.6uA    441.3uA    848.3uA
-1.2V     2.424mA    1.182mA    4.185mA
-1.036V   5.748mA    2.058mA    13.02mA
-872.7mV  15.88mA    5.165mA    23.42mA
-709.1mV  14.53mA    8.476mA    20.05mA
327.3mV   -5.597mA   -3.09mA    -7.989mA
1.091V    -12.45mA   -6.301mA   -17.97mA
2.291V    -14.07mA   -6.77mA    -20.7mA
2.618V    -14.08mA   -1.459mA   -20.97mA
2.782V    -5.908mA   -790.9uA   -20.94mA
3V        -1.582mA   -477.1uA   -4.382mA
3.545V    -498.1uA   -234.4uA   -720.4uA
[GND_clamp]
|   voltage   I(typ)   I(min)   I(max)
-1.8V     -7.797A    -8.671A    -7.298A
-1.218V   -2.297A    -3.197A    -1.772A
-1.182V   -1.974A    -2.871A    -1.452A
-1.145V   -1.654A    -2.548A    -1.137A
-1.073V   -1.052A    -1.92A     -571.9mA
-1.036V   -766.3mA   -1.614A    -322.9mA
-963.6mV  -312.3mA   -1.045A    -73.38mA
-927.3mV  -142mA     -777.3mA   -31.02mA
-854.5mV  -30.45mA   -352.7mA   -17mA
-818.2mV  -14.92mA   -188mA     -13.02mA
-709.1mV  -5.143mA   -18.23mA   -4.527mA
1.764V    -762pA     512.6nA    -26.24pA
[Ramp]
| variable   typ   min   max
dV/dt_f  0.3346187/3.229933n   0.1954918/6.135742n   0.4675346/2.166847n
dV/dt_r  0.3801116/3.467315n   0.1934179/5.944121n   0.5258701/2.238958n
R_load = 50
[Rising Waveform]
R_fixture = 50
V_fixture = 0
V_fixture_min = 0
V_fixture_max = 0
|   time   V(typ)   V(min)   V(max)
0s        3.098mV    -366.7uV   13.92mV
390ps     23.39mV    4.485mV    51.71mV
1.305ns   102.1mV    19.48mV    280.3mV
3ns       298.8mV    66.63mV    676.4mV
3.681ns   379.3mV    89.46mV    772.3mV
4.503ns   466.4mV    116.2mV    830.4mV
5.928ns   563.6mV    166.2mV    864.6mV
8.055ns   616.4mV    236.8mV    874.5mV
12.47ns   632.2mV    305.9mV    876mV
19.74ns   633mV      320.3mV    876mV
[Rising Waveform]
R_fixture = 50
V_fixture = 1.8
V_fixture_min = 1.62
V_fixture_max = 1.89
|   time   V(typ)   V(min)   V(max)
0s        1.251V     1.3V       1.124V
294ps     1.26V      1.3V       1.19V
360ps     1.262V     1.3V       1.289V
555ps     1.326V     1.301V     1.76V
672ps     1.464V     1.301V     1.862V
870ps     1.722V     1.305V     1.885V
975ps     1.777V     1.315V     1.887V
1.152ns   1.795V     1.362V     1.887V
1.674ns   1.798V     1.598V     1.888V
2.346ns   1.798V     1.618V     1.889V
[Falling Waveform]
R_fixture = 50
V_fixture = 0
V_fixture_min = 0
V_fixture_max = 0
|   time   V(typ)   V(min)   V(max)
0s        633.3mV    322.1mV    881mV
114ps     640.9mV    322.4mV    843.7mV
228ps     598.5mV    328.3mV    650.6mV
453ps     354mV      308.7mV    182.8mV
531ps     264.6mV    285.9mV    87.27mV
618ps     176.4mV    255mV      31.96mV
777ps     64.62mV    194.5mV    6.464mV
960ps     12.95mV    130.5mV    2.301mV
1.497ns   1.257mV    17.06mV    1.066mV
2.22ns    846.8uV    1.627mV    664.1uV
[Falling Waveform]
R_fixture = 50
V_fixture = 1.8
V_fixture_min = 1.62
V_fixture_max = 1.89
|   time   V(typ)   V(min)   V(max)
0s        1.801V     1.619V     1.897V
393ps     1.805V     1.624V     1.853V
1.053ns   1.73V      1.618V     1.73V
2.103ns   1.64V      1.579V     1.463V
2.892ns   1.54V      1.566V     1.312V
3.735ns   1.446V     1.544V     1.218V
4.809ns   1.362V     1.505V     1.16V
7.05ns    1.282V     1.423V     1.127V
10.99ns   1.254V     1.338V     1.121V
22.88ns   1.251V     1.301V     1.121V
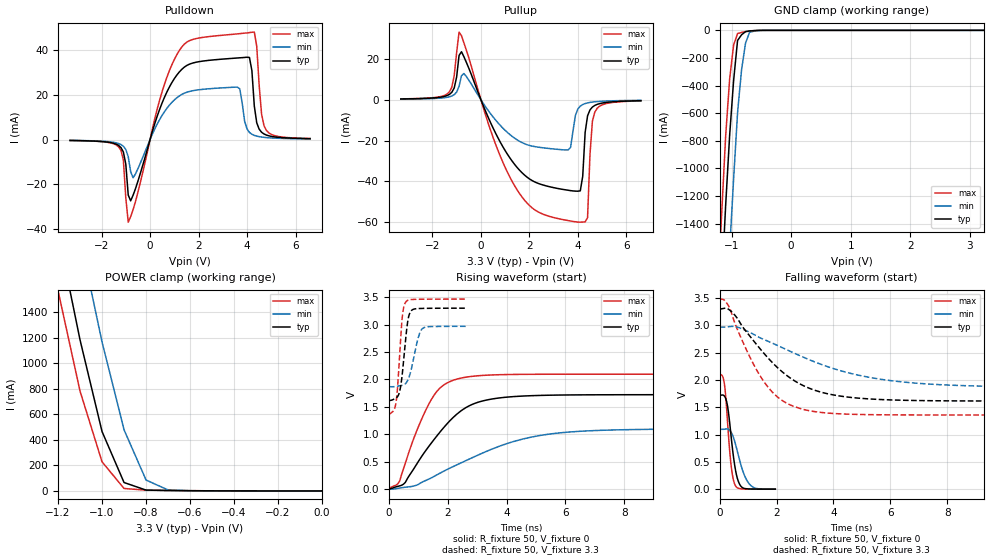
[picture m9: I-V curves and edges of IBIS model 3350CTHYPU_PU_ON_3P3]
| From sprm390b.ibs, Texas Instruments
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|   Model Cell 3350CTHYPU_PU_ON_3P3
|BC3350CTHYPU_PU_ON_3P3
[Model]   3350CTHYPU_PU_ON_3P3
Model_type   I/O
Polarity   Non-Inverting
Enable   Active-Low
Vinl =  0.8V
Vinh =  2V
Cref =  15.0000pF
Rref =  100.0000M
Vref =  0V
Vmeas =  1.65
C_comp   0.8695239p   0.8584917p   0.8767304p
[Model Spec]
Vinl   0.8V   0.8V   0.8V
Vinh   2V   2V   2V
[Temperature Range]   25   125   -40
[Voltage Range]   3.3   2.97   3.465
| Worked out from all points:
|   slope of the pulldown table from 0 to 0.495 V, typ, clamps not added: 30.2 ohm
|   slope of the pullup table from 0 to 0.495 V, typ, clamps not added: 36.2 ohm
|   GND clamp passes 1 mA (typ) near -0.57 V on its own axis
|   POWER clamp passes 1 mA (typ) near -0.52 V on its own axis
|   rising waveform, R_fixture 50, V_fixture 0: 20-80 % time 1.52ns typ, 2.8ns min, 963ps max; typ from 0.003 V to 1.72 V
|   rising waveform, R_fixture 50, V_fixture 3.3: 20-80 % time 194ps typ, 279ps min, 156ps max; typ from 1.62 V to 3.3 V
|   falling waveform, R_fixture 50, V_fixture 0: 20-80 % time 243ps typ, 372ps min, 191ps max; typ from 1.72 V to 0.004 V
|   falling waveform, R_fixture 50, V_fixture 3.3: 20-80 % time 1.92ns typ, 3.35ns min, 1.32ns max; typ from 3.3 V to 1.62 V
[POWER_clamp]
|   voltage   I(typ)   I(min)   I(max)
-3.3V     22.37A     23.12A     21.96A
-1.2V     2.026A     2.853A     1.569A
-1.167V   1.745A     2.562A     1.307A
-1.133V   1.464A     2.272A     1.044A
-1.1V     1.183A     1.981A     781.9mA
-1.067V   943.8mA    1.709A     597.3mA
-1.033V   704.5mA    1.438A     412.6mA
-1V       465.3mA    1.167A     228mA
-900mV    65.81mA    478.8mA    19.07mA
-800mV    6.532mA    85.44mA    6.185mA
-700mV    3.207mA    7.588mA    3.913mA
0V        276.4pA    13.39nA    14.62pA
[Pulldown]
|   voltage   I(typ)   I(min)   I(max)
-3.3V     -379.4uA   -330.9uA   -386.9uA
-1.3V     -2.568mA   -1.749mA   -3.18mA
-1.1V     -5.533mA   -2.961mA   -9.162mA
-900mV    -24.8mA    -7.62mA    -36.98mA
-700mV    -24.92mA   -17.08mA   -31.4mA
1.2V      30.22mA    19.51mA    39.79mA
3.6V      36.57mA    23.5mA     47.37mA
4.1V      36.79mA    3.231mA    47.94mA
4.3V      15.06mA    1.903mA    48.17mA
4.6V      3.307mA    1.155mA    11.41mA
4.8V      2.043mA    911.4uA    4.087mA
6.6V      436uA      308.8uA    502.3uA
[Pullup]
|   voltage   I(typ)   I(min)   I(max)
-3.3V     352.6uA    257.6uA    391.7uA
-1.3V     2.559mA    1.411mA    3.79mA
-900mV    21.62mA    6.558mA    33.08mA
-700mV    21.01mA    12.8mA     27.85mA
500mV     -13.79mA   -8.403mA   -18.35mA
1.5V      -33.25mA   -19.7mA    -44.26mA
3.6V      -44.33mA   -24.58mA   -59.17mA
4.1V      -44.61mA   -3.141mA   -59.96mA
4.4V      -7.897mA   -1.57mA    -57.69mA
4.5V      -4.997mA   -1.34mA    -26.74mA
4.7V      -2.803mA   -1.033mA   -6.023mA
6.6V      -515.4uA   -319.6uA   -597.7uA
[GND_clamp]
|   voltage   I(typ)   I(min)   I(max)
-3.3V     -22.52A    -23.33A    -22.07A
-1.233V   -2.436A    -3.336A    -1.911A
-1.167V   -1.845A    -2.739A    -1.328A
-1.1V     -1.269A    -2.151A    -766.5mA
-1.033V   -763.9mA   -1.597A    -354.9mA
-966.7mV  -365.3mA   -1.079A    -107.2mA
-900mV    -73.61mA   -596.8mA   -23.43mA
-833.3mV  -32.7mA    -287.4mA   -15.45mA
-766.7mV  -9.755mA   -93.52mA   -9.034mA
-700mV    -4.785mA   -15.17mA   -4.166mA
-433.3mV  -172.1uA   -326.3uA   -169.2uA
3.233V    -4.892uA   24.61uA    -22.8uA
[Ramp]
| variable   typ   min   max
dV/dt_f   1.020715/1.927181n   0.6697412/3.394734n   1.273669/1.32105n
dV/dt_r   1.032187/1.519465n   0.6584636/2.812143n   1.256079/0.9663692n
R_load = 50
[Rising Waveform]
R_fixture = 50
V_fixture = 0
V_fixture_min = 0
V_fixture_max = 0
|   time   V(typ)   V(min)   V(max)
0s        2.929mV    892.6uV    14.8mV
372ps     61.38mV    21.59mV    155mV
558ps     122.6mV    35.98mV    471.5mV
927ps     440.3mV    70.17mV    1.037V
1.488ns   871.7mV    219.2mV    1.672V
1.782ns   1.07V      304.7mV    1.864V
2.202ns   1.314V     416.6mV    1.987V
3.309ns   1.623V     687.1mV    2.077V
5.478ns   1.713V     1.006V     2.094V
11.41ns   1.722V     1.095V     2.095V
[Rising Waveform]
R_fixture = 50
V_fixture = 3.3
V_fixture_min = 2.97
V_fixture_max = 3.465
|   time   V(typ)   V(min)   V(max)
0s        1.616V     1.867V     1.367V
237ps     1.66V      1.872V     1.562V
291ps     1.684V     1.877V     1.823V
366ps     1.781V     1.885V     2.434V
456ps     2.099V     1.893V     3.134V
570ps     2.727V     1.925V     3.407V
651ps     3.088V     1.995V     3.443V
726ps     3.224V     2.111V     3.453V
1.122ns   3.293V     2.918V     3.461V
2.625ns   3.298V     2.967V     3.464V
[Falling Waveform]
R_fixture = 50
V_fixture = 0
V_fixture_min = 0
V_fixture_max = 0
|   time   V(typ)   V(min)   V(max)
0s        1.722V     1.098V     2.096V
150ps     1.716V     1.099V     1.979V
201ps     1.675V     1.104V     1.764V
252ps     1.588V     1.106V     1.417V
336ps     1.289V     1.088V     802.3mV
402ps     967.3mV    1.047V     439.6mV
546ps     382.9mV    844.3mV    75.42mV
726ps     71.58mV    484.8mV    11.14mV
1.029ns   7.585mV    107.1mV    5.187mV
1.956ns   3.602mV    4.239mV    3.231mV
[Falling Waveform]
R_fixture = 50
V_fixture = 3.3
V_fixture_min = 2.97
V_fixture_max = 3.465
|   time   V(typ)   V(min)   V(max)
0s        3.299V     2.97V      3.471V
153ps     3.313V     2.969V     3.468V
306ps     3.298V     2.976V     3.364V
996ps     2.847V     2.888V     2.492V
1.611ns   2.456V     2.73V      1.931V
2.154ns   2.171V     2.605V     1.643V
2.841ns   1.924V     2.442V     1.477V
4.233ns   1.708V     2.174V     1.382V
6.51ns    1.63V      1.961V     1.362V
14.66ns   1.616V     1.87V      1.361V
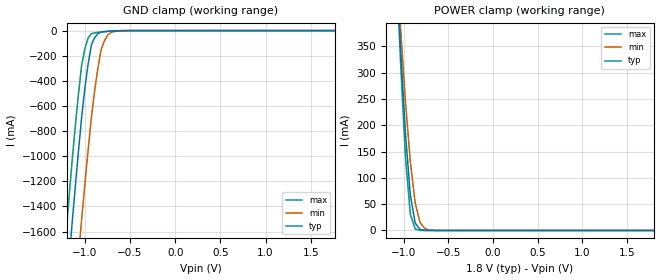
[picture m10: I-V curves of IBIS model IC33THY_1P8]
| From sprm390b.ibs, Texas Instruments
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|   Model Cell IC33THY_1P8
|IC33THY_1P8
[Model]   IC33THY_1P8
Model_type   Input
Polarity   Non-Inverting
Vinl =  0.63
Vinh =  1.17
C_comp   0.9057833p   0.8873771p   0.9227325p
[Model Spec]
Vinl   0.63   0.567   0.6615
Vinh   1.17   1.053   1.2285
[Temperature Range]   25   125   -40
[Voltage Range]   1.8   1.62   1.89
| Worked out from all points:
|   GND clamp passes 1 mA (typ) near -0.60 V on its own axis
|   POWER clamp passes 1 mA (typ) near -0.79 V on its own axis
[POWER_clamp]
|   voltage   I(typ)   I(min)   I(max)
-1.8V     3.329A     2.868A     3.753A
-1.055V   406.6mA    435.7mA    391.1mA
-1.036V   345.5mA    384.7mA    320.4mA
-1.018V   291.9mA    338.5mA    260.4mA
-981.8mV  184.8mA    246.1mA    140.4mA
-927.3mV  67.55mA    131mA      30.67mA
-872.7mV  14.03mA    52.53mA    2.925mA
-818.2mV  1.995mA    15.23mA    215.2uA
-763.6mV  257.7uA    3.582mA    15.43uA
-709.1mV  32.83uA    782.3uA    1.105uA
1.8V      49.46pA    5.096nA    797.1fA
[GND_clamp]
|   voltage   I(typ)   I(min)   I(max)
-1.8V     -7.705A    -8.549A    -7.226A
-1.218V   -2.212A    -3.083A    -1.707A
-1.182V   -1.89A     -2.758A    -1.388A
-1.145V   -1.572A    -2.436A    -1.075A
-1.073V   -976.6mA   -1.813A    -520.4mA
-1.036V   -696.3mA   -1.51A     -280.4mA
-963.6mV  -265.3mA   -950.9mA   -58.96mA
-927.3mV  -112mA     -690.9mA   -24.83mA
-854.5mV  -23.27mA   -293.6mA   -13.66mA
-818.2mV  -11.72mA   -147mA     -10.45mA
-709.1mV  -4.117mA   -13.44mA   -3.621mA
1.764V    47.68pA    5.64nA     621fA
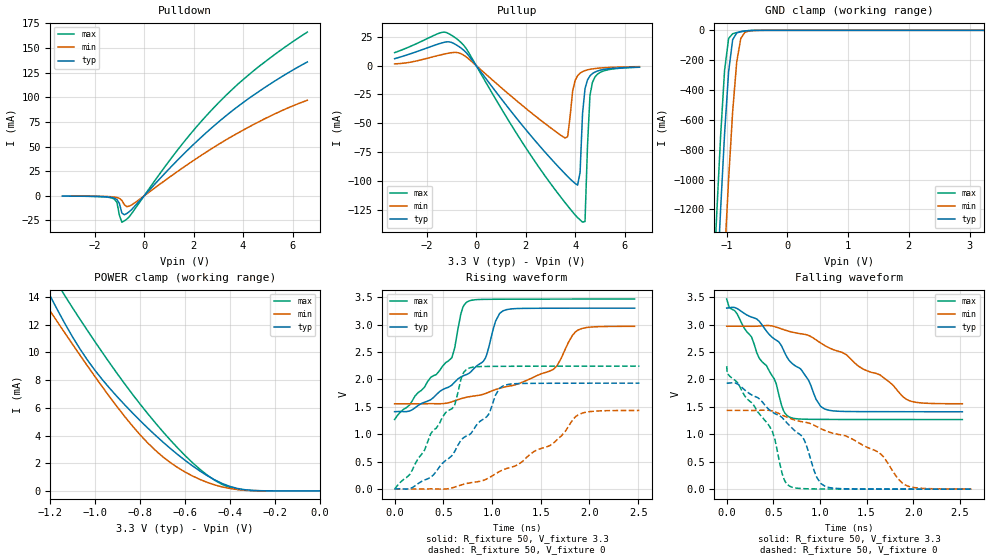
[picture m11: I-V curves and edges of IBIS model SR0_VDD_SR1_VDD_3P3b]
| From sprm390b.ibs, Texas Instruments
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|SR0_VSS_SR1_VSS_3P3CELL OPERATING IN SLOW MODE
|   Model Cell SR0_VDD_SR1_VDD_3P3b
|SR0_VDD_SR1_VDD_3P3b
[Model]   SR0_VDD_SR1_VDD_3P3b
Model_type   3-state
Polarity   Non-Inverting
Enable   Active-Low
Cref =  5.0000pF
Rref =  100.0000M
Vref =  0V
Vmeas =  1.65
C_comp   1.985348p   1.918512p   2.114271p
[Temperature Range]   25   125   -40
[Voltage Range]   3.3   2.97   3.465
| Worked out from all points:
|   slope of the pulldown table from 0 to 0.495 V, typ, clamps not added: 36.4 ohm
|   slope of the pullup table from 0 to 0.495 V, typ, clamps not added: 34.9 ohm
|   GND clamp passes 1 mA (typ) near -0.57 V on its own axis
|   POWER clamp passes 1 mA (typ) near -0.49 V on its own axis
|   rising waveform, R_fixture 50, V_fixture 3.3: 20-80 % time 542ps typ, 711ps min, 446ps max; typ from 1.41 V to 3.3 V
|   rising waveform, R_fixture 50, V_fixture 0: 20-80 % time 550ps typ, 740ps min, 446ps max; typ from 0 V to 1.93 V
|   falling waveform, R_fixture 50, V_fixture 3.3: 20-80 % time 515ps typ, 823ps min, 401ps max; typ from 3.3 V to 1.41 V
|   falling waveform, R_fixture 50, V_fixture 0: 20-80 % time 525ps typ, 840ps min, 409ps max; typ from 1.93 V to 0.001 V
[POWER_clamp]
|   voltage   I(typ)   I(min)   I(max)
-3.3V     86.08mA    64.51mA    104.3mA
-1.267V   16.23mA    14.61mA    17.94mA
-1.233V   15.14mA    13.79mA    16.86mA
-1.2V     14.07mA    12.98mA    15.86mA
-1.133V   12.04mA    11.37mA    14.06mA
-1V       8.693mA    8.239mA    10.76mA
-866.7mV  6.192mA    5.342mA    7.695mA
-766.7mV  4.556mA    3.483mA    5.603mA
-633.3mV  2.644mA    1.698mA    3.12mA
-500mV    1.095mA    613.5uA    1.135mA
-366.7mV  181.9uA    101.9uA    111.4uA
-11.55fV  449.1nA    420.7nA    471.2nA
[Pulldown]
|   voltage   I(typ)   I(min)   I(max)
-3.3V     -240.7uA   -171.6uA   -267.4uA
-1.3V     -1.696mA   -967.9uA   -2.238mA
-1.1V     -3.76mA    -1.687mA   -6.633mA
-1V       -7.724mA   -2.566mA   -19.64mA
-900mV    -17.44mA   -4.636mA   -26.73mA
-800mV    -19.19mA   -8.992mA   -25.4mA
-700mV    -17.88mA   -11mA      -23.57mA
-500mV    -13.74mA   -9.146mA   -17.83mA
1.4V      37.42mA    25.57mA    48.03mA
2.9V      72.6mA     50.52mA    91.53mA
4.6V      105.1mA    74.64mA    130.4mA
6.6V      135.8mA    96.92mA    166.1mA
[Pullup]
|   voltage   I(typ)   I(min)   I(max)
-3.3V     6.015mA    1.488mA    11.26mA
-1.4V     19.63mA    9.503mA    28.79mA
-700mV    16.55mA    11.01mA    21.71mA
3.6V      -93.97mA   -62.77mA   -119mA
4.1V      -103.6mA   -8.734mA   -131.8mA
4.2V      -92.67mA   -6.55mA    -133.7mA
4.3V      -41.54mA   -5.211mA   -135.8mA
4.4V      -19.9mA    -4.314mA   -135.1mA
4.5V      -12.39mA   -3.675mA   -69.69mA
4.6V      -8.867mA   -3.197mA   -25.85mA
4.7V      -6.863mA   -2.828mA   -14.55mA
6.6V      -1.25mA    -873.6uA   -1.41mA
[GND_clamp]
|   voltage   I(typ)   I(min)   I(max)
-3.3V     -22.46A    -23.25A    -22.02A
-1.233V   -2.372A    -3.255A    -1.856A
-1.167V   -1.78A     -2.658A    -1.268A
-1.1V     -1.214A    -2.077A    -719.1mA
-1.033V   -694.7mA   -1.519A    -268.7mA
-966.7mV  -277.4mA   -998mA     -54.36mA
-900mV    -62.56mA   -543.6mA   -22.84mA
-833.3mV  -17.57mA   -212.4mA   -14.86mA
-766.7mV  -9.139mA   -55.16mA   -8.916mA
-700mV    -5.031mA   -13.73mA   -4.378mA
-633.3mV  -2.323mA   -4.775mA   -1.567mA
3.233V    432.4nA    13.42uA    421.6nA
[Ramp]
| variable   typ   min   max
dV/dt_f   1.523838/0.6824025n   1.143085/1.116329n   1.769688/0.5147569n
dV/dt_r   1.547193/0.6947426n   1.150736/0.9649163n   1.794899/0.5498306n
R_load = 50
[Rising Waveform]
R_fixture = 50
V_fixture = 3.3
V_fixture_min = 2.97
V_fixture_max = 3.465
|   time   V(typ)   V(min)   V(max)
0s        1.411V     1.554V     1.269V
588ps     1.896V     1.591V     2.395V
679ps     2.043V     1.647V     3.186V
749ps     2.096V     1.678V     3.417V
931ps     2.385V     1.741V     3.46V
1.036ns   3.06V      1.814V     3.461V
1.113ns   3.25V      1.854V     3.462V
1.631ns   3.298V     2.183V     3.464V
1.904ns   3.299V     2.917V     3.464V
2.464ns   3.299V     2.967V     3.465V
[Rising Waveform]
R_fixture = 50
V_fixture = 0
V_fixture_min = 0
V_fixture_max = 0
|   time   V(typ)   V(min)   V(max)
0s        5.618uV    6.875uV    4.844uV
154ps     4.552mV    -40.61uV   261.7mV
371ps     214.7mV    2.983mV    1.009V
616ps     682mV      34.9mV     1.525V
679ps     882.8mV    71.03mV    1.991V
749ps     975.1mV    104mV      2.193V
1.155ns   1.904V     377mV      2.239V
1.631ns   1.929V     838.7mV    2.24V
1.89ns    1.93V      1.358V     2.241V
2.513ns   1.931V     1.433V     2.241V
[Falling Waveform]
R_fixture = 50
V_fixture = 3.3
V_fixture_min = 2.97
V_fixture_max = 3.465
|   time   V(typ)   V(min)   V(max)
0s        3.3V       2.97V      3.465V
322ps     3.102V     2.97V      2.49V
511ps     2.738V     2.964V     2.009V
609ps     2.537V     2.909V     1.433V
665ps     2.359V     2.879V     1.322V
812ps     2.149V     2.828V     1.277V
1.05ns    1.461V     2.619V     1.272V
1.645ns   1.413V     2.082V     1.27V
1.96ns    1.412V     1.611V     1.269V
2.527ns   1.411V     1.557V     1.269V
[Falling Waveform]
R_fixture = 50
V_fixture = 0
V_fixture_min = 0
V_fixture_max = 0
|   time   V(typ)   V(min)   V(max)
0s        1.931V     1.436V     2.241V
490ps     1.404V     1.425V     1.052V
595ps     1.304V     1.351V     281.7mV
686ps     1.14V      1.285V     45.87mV
819ps     934.5mV    1.226V     9.87mV
966ps     217mV      1.14V      4.64mV
1.057ns   50.02mV    1.067V     3.561mV
1.631ns   2.553mV    672.1mV    1.095mV
1.946ns   1.516mV    53.82mV    609.3uV
2.625ns   670.2uV    3.021mV    230uV
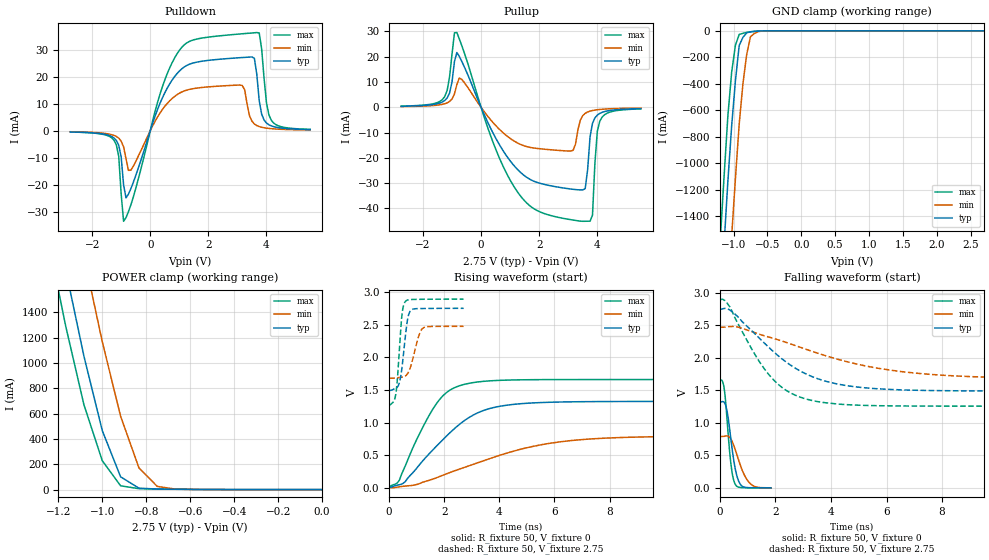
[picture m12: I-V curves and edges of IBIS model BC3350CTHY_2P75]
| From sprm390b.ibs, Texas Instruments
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|CELL IN NORMAL MODE AT 3.3 NOM VOLTAGE
|   Model Cell BC3350CTHY_2P75
|BC3350CTHY_2P75
[Model]   BC3350CTHY_2P75
Model_type   I/O
Polarity   Non-Inverting
Enable   Active-Low
Vinl =  0.7V
Vinh =  1.7V
Cref =  15.0000pF
Rref =  100.0000M
Vref =  0V
Vmeas =  1.375
C_comp   0.8815254p   0.8700002p   0.8886429p
[Model Spec]
Vinl   0.7V   0.7V   0.7V
Vinh   1.7V   1.7V   1.7V
[Temperature Range]   25   125   -40
[Voltage Range]   2.75   2.475   2.89
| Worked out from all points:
|   slope of the pulldown table from 0 to 0.412 V, typ, clamps not added: 34.2 ohm
|   slope of the pullup table from 0 to 0.412 V, typ, clamps not added: 40.5 ohm
|   GND clamp passes 1 mA (typ) near -0.59 V on its own axis
|   POWER clamp passes 1 mA (typ) near -0.52 V on its own axis
|   rising waveform, R_fixture 50, V_fixture 0: 20-80 % time 1.9ns typ, 3.45ns min, 1.2ns max; typ from 0.002 V to 1.32 V
|   rising waveform, R_fixture 50, V_fixture 2.75: 20-80 % time 206ps typ, 301ps min, 163ps max; typ from 1.49 V to 2.75 V
|   falling waveform, R_fixture 50, V_fixture 0: 20-80 % time 262ps typ, 414ps min, 201ps max; typ from 1.32 V to 0.001 V
|   falling waveform, R_fixture 50, V_fixture 2.75: 20-80 % time 2.21ns typ, 3.92ns min, 1.52ns max; typ from 2.75 V to 1.49 V
[POWER_clamp]
|   voltage   I(typ)   I(min)   I(max)
-2.75V    16.94A     17.72A     16.52A
-1.194V   1.981A     2.806A     1.529A
-1.139V   1.509A     2.319A     1.084A
-1.083V   1.051A     1.84A      668.4mA
-1.056V   856mA      1.616A     521.6mA
-1.028V   660.6mA    1.391A     374.7mA
-1V       465.3mA    1.167A     227.9mA
-916.7mV  101mA      578.9mA    30.07mA
-833.3mV  11.42mA    171.8mA    7.264mA
-750mV    4.141mA    25.39mA    4.875mA
-666.7mV  2.647mA    3.743mA    3.197mA
0V        162.7pA    10.29nA    5.769pA
[Pulldown]
|   voltage   I(typ)   I(min)   I(max)
-2.75V    -442uA     -372.3uA   -461.5uA
-1.25V    -2.654mA   -1.707mA   -3.463mA
-1.083V   -5.414mA   -2.743mA   -9.571mA
-916.7mV  -20.11mA   -6.002mA   -33.59mA
-666.7mV  -21.47mA   -14.63mA   -27.52mA
1V        22.12mA    13.91mA    29.78mA
3.167V    27.16mA    16.8mA     35.98mA
3.667V    20.89mA    1.926mA    36.42mA
3.833V    6.157mA    1.295mA    30.36mA
4V        2.871mA    968.4uA    10.33mA
4.167V    1.802mA    770.5uA    3.863mA
5.5V      426.6uA    287.2uA    512.6uA
[Pullup]
|   voltage   I(typ)   I(min)   I(max)
-2.75V    418.2uA    298uA      474.9uA
-1.25V    2.701mA    1.416mA    4.261mA
-833.3mV  21.66mA    8.993mA    29.57mA
416.7mV   -10.28mA   -6.093mA   -13.97mA
1.167V    -23.49mA   -13.53mA   -31.97mA
3.167V    -32.42mA   -16.99mA   -44.58mA
3.5V      -32.66mA   -3.265mA   -45.07mA
3.583V    -32.13mA   -2.367mA   -45.05mA
3.833V    -6.324mA   -1.256mA   -42.67mA
4V        -3.056mA   -947.9uA   -9.45mA
4.083V    -2.401mA   -843.3uA   -5.52mA
5.5V      -494.4uA   -288.5uA   -602.6uA
[GND_clamp]
|   voltage   I(typ)   I(min)   I(max)
-2.75V    -17.09A    -17.92A    -16.63A
-1.194V   -2.087A    -2.985A    -1.564A
-1.139V   -1.603A    -2.493A    -1.092A
-1.083V   -1.133A    -2.009A    -639.3mA
-1.028V   -718.3mA   -1.55A     -312.4mA
-972.2mV  -377.6mA   -1.115A    -108.5mA
-916.7mV  -110.7mA   -705.2mA   -27.3mA
-861.1mV  -49.1mA    -398.2mA   -18.78mA
-805.6mV  -14.74mA   -178.1mA   -12.09mA
-750mV    -7.591mA   -44.83mA   -7.219mA
-638.9mV  -2.45mA    -6.09mA    -1.79mA
2.694V    -702.4pA   3.817uA    -24.73pA
[Ramp]
| variable   typ   min   max
dV/dt_f  0.7640286/2.222784n   0.4843343/3.9849n   0.9886006/1.527886n
dV/dt_r  0.7939512/1.905165n   0.475601/3.469632n   0.9950265/1.202795n
R_load = 50
[Rising Waveform]
R_fixture = 50
V_fixture = 0
V_fixture_min = 0
V_fixture_max = 0
|   time   V(typ)   V(min)   V(max)
0s        1.775mV    -423.6uV   15.24mV
369ps     47.24mV    15.32mV    115.4mV
1.035ns   319mV      54.5mV     770.4mV
1.701ns   630.4mV    151.4mV    1.279V
2.091ns   796.1mV    216.2mV    1.461V
2.613ns   991.7mV    295.5mV    1.571V
3.177ns   1.141V     377.8mV    1.619V
3.888ns   1.238V     480.3mV    1.643V
6.525ns   1.316V     720.1mV    1.658V
13.19ns   1.323V     789.7mV    1.658V
[Rising Waveform]
R_fixture = 50
V_fixture = 2.75
V_fixture_min = 2.475
V_fixture_max = 2.89
|   time   V(typ)   V(min)   V(max)
0s        1.491V     1.678V     1.264V
240ps     1.526V     1.682V     1.434V
297ps     1.543V     1.686V     1.657V
369ps     1.608V     1.69V      2.097V
462ps     1.83V      1.694V     2.636V
579ps     2.282V     1.708V     2.848V
657ps     2.55V      1.741V     2.874V
741ps     2.687V     1.81V      2.881V
1.197ns   2.745V     2.436V     2.887V
2.703ns   2.748V     2.473V     2.889V
[Falling Waveform]
R_fixture = 50
V_fixture = 0
V_fixture_min = 0
V_fixture_max = 0
|   time   V(typ)   V(min)   V(max)
0s        1.323V     792.3mV    1.66V
132ps     1.324V     792.8mV    1.577V
183ps     1.294V     796.6mV    1.42V
234ps     1.223V     800.7mV    1.169V
384ps     781mV      758.3mV    406.3mV
459ps     533.7mV    693.5mV    183.1mV
537ps     322.5mV    603.6mV    66.31mV
741ps     51.93mV    340.6mV    6.294mV
1.074ns   3.529mV    73.47mV    1.846mV
1.836ns   1.306mV    2.497mV    952.5uV
[Falling Waveform]
R_fixture = 50
V_fixture = 2.75
V_fixture_min = 2.475
V_fixture_max = 2.89
|   time   V(typ)   V(min)   V(max)
0s        2.749V     2.475V     2.897V
177ps     2.764V     2.475V     2.884V
354ps     2.739V     2.483V     2.787V
1.236ns   2.382V     2.393V     2.07V
1.854ns   2.126V     2.311V     1.698V
2.478ns   1.909V     2.226V     1.478V
3.273ns   1.721V     2.109V     1.35V
4.827ns   1.559V     1.916V     1.276V
7.497ns   1.5V       1.75V      1.259V
16.31ns   1.491V     1.681V     1.258V
